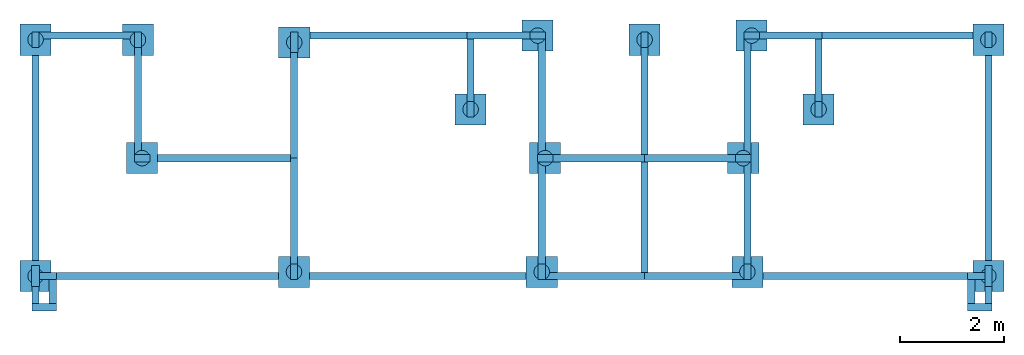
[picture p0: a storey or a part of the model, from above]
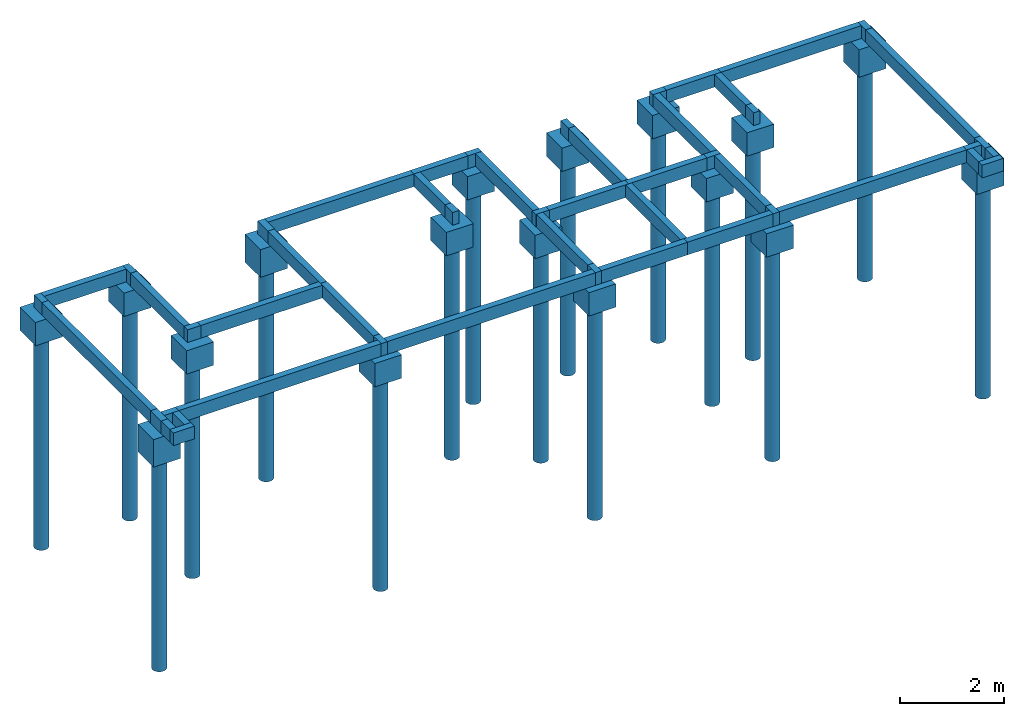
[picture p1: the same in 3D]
Properties of the parts of a building model (IFC4)

# File
Description: IFC4
Time: 2025-08-22T16:06:54
Made in: IfcPlusPlus

# IfcBuildingStorey (3)
Name | LongName | Elevation (cm)
BALDRAME (FUNDAÇÃO) | BALDRAME (FUNDAÇÃO) | 2
RESPALDO | RESPALDO | 312
PLANTIBANDA | PLANTIBANDA | 372

# IfcBeam (87)
Material: Concreto
Pset_ConcreteElementGeneral - ConcreteCover: 3 cm; ConstructionMethod: InSitu; ExposureClass: 2; StrengthClass: C-25
AltoQi_Eberick_Elemento - Elemento: Viga; Tipo: retangular
AltoQi_Eberick_Padrão - Ambiente: Externo; Cobrimento: 3 cm; Classe de concreto: C-25
AltoQi_Eberick_Cargas - Adicional (G2): 0; Solo (S): 0; Acidental (Q): 0; Água (A): 0; Subpressão (AS): 0
Pset_BeamCommon - IsExternal: yes; LoadBearing: yes
Name | In | Seção_bw (cm) | Seção_h (cm) | Elevação (cm) | Taxa de armadura | Cargas de parede (G2) | Reference
V1 | BALDRAME (FUNDAÇÃO) | 14 | 30 | 0 | 0.24 % | 526.5 | Viga C-25 - Seção Retangular 14 X 30
2 x V10 | BALDRAME (FUNDAÇÃO) | 14 | 30 | 0 | 0.24 % | 526.5 | Viga C-25 - Seção Retangular 14 X 30
2 x V11 | BALDRAME (FUNDAÇÃO) | 14 | 30 | 0 | 0.24 % | 526.5 | Viga C-25 - Seção Retangular 14 X 30
2 x V12 | BALDRAME (FUNDAÇÃO) | 14 | 30 | 0 | 0.24 % | 526.5 | Viga C-25 - Seção Retangular 14 X 30
V13 | BALDRAME (FUNDAÇÃO) | 14 | 30 | 0 | 0.24 % | 571.32 | Viga C-25 - Seção Retangular 14 X 30
2 x V14 | BALDRAME (FUNDAÇÃO) | 14 | 30 | 0 | 0.24 % | 526.5 | Viga C-25 - Seção Retangular 14 X 30
2 x V14 | BALDRAME (FUNDAÇÃO) | 14 | 30 | 0 | 0.24 % | 0 | Viga C-25 - Seção Retangular 14 X 30
2 x V15 | BALDRAME (FUNDAÇÃO) | 14 | 30 | 0 | 0.24 % | 526.5 | Viga C-25 - Seção Retangular 14 X 30
2 x V15 | BALDRAME (FUNDAÇÃO) | 14 | 30 | 0 | 0.24 % | 0 | Viga C-25 - Seção Retangular 14 X 30
2 x V2 | BALDRAME (FUNDAÇÃO) | 14 | 30 | 0 | 0.24 % | 526.5 | Viga C-25 - Seção Retangular 14 X 30
2 x V3 | BALDRAME (FUNDAÇÃO) | 14 | 30 | 0 | 0.24 % | 526.5 | Viga C-25 - Seção Retangular 14 X 30
V4 | BALDRAME (FUNDAÇÃO) | 14 | 30 | 0 | 0.24 % | 526.5 | Viga C-25 - Seção Retangular 14 X 30
2 x V5 | BALDRAME (FUNDAÇÃO) | 14 | 30 | 0 | 0.36 % | 526.5 | Viga C-25 - Seção Retangular 14 X 30
7 x V6 | BALDRAME (FUNDAÇÃO) | 14 | 30 | 0 | 0.24 % | 526.5 | Viga C-25 - Seção Retangular 14 X 30
V7 | BALDRAME (FUNDAÇÃO) | 14 | 30 | 0 | 0.24 % | 526.5 | Viga C-25 - Seção Retangular 14 X 30
2 x V8 | BALDRAME (FUNDAÇÃO) | 14 | 30 | 0 | 0.36 % | 526.5 | Viga C-25 - Seção Retangular 14 X 30
V9 | BALDRAME (FUNDAÇÃO) | 14 | 30 | 0 | 0.24 % | 526.5 | Viga C-25 - Seção Retangular 14 X 30
5 x V1 | RESPALDO | 15 | 40 | 0 | 0.17 % | 0 | Viga C-25 - Seção Retangular 15 X 40
2 x V1 | RESPALDO | 15 | 40 | 0 | 0.25 % | 0 | Viga C-25 - Seção Retangular 15 X 40
V1 | RESPALDO | 15 | 40 | 0 | 0.34 % | 0 | Viga C-25 - Seção Retangular 15 X 40
2 x V10 | RESPALDO | 14 | 30 | 0 | 0.24 % | 0 | Viga C-25 - Seção Retangular 14 X 30
V10 | RESPALDO | 14 | 30 | 0 | 0.24 % | 97.5 | Viga C-25 - Seção Retangular 14 X 30
2 x V11 | RESPALDO | 14 | 30 | 0 | 0.24 % | 0 | Viga C-25 - Seção Retangular 14 X 30
2 x V12 | RESPALDO | 14 | 30 | 0 | 0.24 % | 0 | Viga C-25 - Seção Retangular 14 X 30
V12 | RESPALDO | 14 | 30 | 0 | 0.24 % | 97.5 | Viga C-25 - Seção Retangular 14 X 30
V13 | RESPALDO | 14 | 30 | 0 | 0.24 % | 0 | Viga C-25 - Seção Retangular 14 X 30
4 x V14 | RESPALDO | 14 | 40 | 0 | 0.18 % | 0 | Viga C-25 - Seção Retangular 14 X 40
4 x V15 | RESPALDO | 14 | 40 | 0 | 0.18 % | 0 | Viga C-25 - Seção Retangular 14 X 40
V2 | RESPALDO | 14 | 30 | 0 | 0.24 % | 0 | Viga C-25 - Seção Retangular 14 X 30
V3 | RESPALDO | 14 | 30 | 0 | 0.24 % | 0 | Viga C-25 - Seção Retangular 14 X 30
V4 | RESPALDO | 14 | 30 | 0 | 0.24 % | 0 | Viga C-25 - Seção Retangular 14 X 30
2 x V5 | RESPALDO | 14 | 30 | 0 | 0.24 % | 97.5 | Viga C-25 - Seção Retangular 14 X 30
7 x V6 | RESPALDO | 14 | 40 | 0 | 0.18 % | 0 | Viga C-25 - Seção Retangular 14 X 40
V7 | RESPALDO | 14 | 30 | 0 | 0.24 % | 0 | Viga C-25 - Seção Retangular 14 X 30
2 x V8 | RESPALDO | 14 | 30 | 0 | 0.24 % | 0 | Viga C-25 - Seção Retangular 14 X 30
V9 | RESPALDO | 14 | 30 | 0 | 0.24 % | 0 | Viga C-25 - Seção Retangular 14 X 30
4 x V1 | PLANTIBANDA | 14 | 30 | 60 | 0.24 % | 0 | Viga C-25 - Seção Retangular 14 X 30
4 x V2 | PLANTIBANDA | 14 | 30 | 60 | 0.24 % | 0 | Viga C-25 - Seção Retangular 14 X 30
2 x V3 | PLANTIBANDA | 14 | 30 | 60 | 0.24 % | 0 | Viga C-25 - Seção Retangular 14 X 30
2 x V4 | PLANTIBANDA | 14 | 30 | 60 | 0.24 % | 0 | Viga C-25 - Seção Retangular 14 X 30

# IfcColumn (46)
Material: Concreto
Pset_ConcreteElementGeneral - ConcreteCover: 3 cm; ConstructionMethod: InSitu; ExposureClass: 2; StrengthClass: C-25
AltoQi_Eberick_Elemento - Elemento: Pilar; Tipo: retangular
AltoQi_Eberick_Padrão - Ambiente: Externo; Cobrimento: 3 cm; Classe de concreto: C-25
Pset_ColumnCommon - IsExternal: yes; LoadBearing: yes
Name | In | Seção_b (cm) | Seção_h (cm) | Elevação (cm) | Taxa de armadura | Taxa de compressão bruta | Taxa de compressão homogeneizada | Reference
P1 | BALDRAME (FUNDAÇÃO) | 14 | 30 | 0 | 0.75 % | 0.09 | 0.08 | Pilar C-25 - Retangular 14x30
P10 | BALDRAME (FUNDAÇÃO) | 14 | 30 | 0 | 0.75 % | 0.07 | 0.06 | Pilar C-25 - Retangular 14x30
P11 | BALDRAME (FUNDAÇÃO) | 14 | 30 | 0 | 1.12 % | 0.1 | 0.08 | Pilar C-25 - Retangular 14x30
P12 | BALDRAME (FUNDAÇÃO) | 14 | 30 | 0 | 1.12 % | 0.1 | 0.08 | Pilar C-25 - Retangular 14x30
P13 | BALDRAME (FUNDAÇÃO) | 15 | 40 | 0 | 1.64 % | 0.09 | 0.07 | Pilar C-25 - Retangular 15x40
P14 | BALDRAME (FUNDAÇÃO) | 14 | 30 | 0 | 0.75 % | 0.18 | 0.15 | Pilar C-25 - Retangular 14x30
P15 | BALDRAME (FUNDAÇÃO) | 14 | 30 | 0 | 0.75 % | 0.14 | 0.12 | Pilar C-25 - Retangular 14x30
P16 | BALDRAME (FUNDAÇÃO) | 14 | 30 | 0 | 0.75 % | 0.15 | 0.12 | Pilar C-25 - Retangular 14x30
P17 | BALDRAME (FUNDAÇÃO) | 14 | 40 | 0 | 1.75 % | 0.1 | 0.08 | Pilar C-25 - Retangular 14x40
P2 | BALDRAME (FUNDAÇÃO) | 14 | 30 | 0 | 0.75 % | 0.06 | 0.05 | Pilar C-25 - Retangular 14x30
P3 | BALDRAME (FUNDAÇÃO) | 15 | 40 | 0 | 1.64 % | 0.1 | 0.08 | Pilar C-25 - Retangular 15x40
P4 | BALDRAME (FUNDAÇÃO) | 14 | 30 | 0 | 0.75 % | 0.1 | 0.08 | Pilar C-25 - Retangular 14x30
P5 | BALDRAME (FUNDAÇÃO) | 14 | 30 | 0 | 1.12 % | 0.05 | 0.04 | Pilar C-25 - Retangular 14x30
P6 | BALDRAME (FUNDAÇÃO) | 14 | 30 | 0 | 0.75 % | 0.1 | 0.08 | Pilar C-25 - Retangular 14x30
P7 | BALDRAME (FUNDAÇÃO) | 14 | 30 | 0 | 2.34 % | 0.12 | 0.09 | Pilar C-25 - Retangular 14x30
P8 | BALDRAME (FUNDAÇÃO) | 14 | 30 | 0 | 1.12 % | 0.06 | 0.05 | Pilar C-25 - Retangular 14x30
P9 | BALDRAME (FUNDAÇÃO) | 14 | 30 | 0 | 1.12 % | 0.06 | 0.05 | Pilar C-25 - Retangular 14x30
P1 | RESPALDO | 14 | 30 | 0 | 0.75 % | 0.05 | 0.05 | Pilar C-25 - Retangular 14x30
P10 | RESPALDO | 14 | 30 | 0 | 0.75 % | 0.04 | 0.03 | Pilar C-25 - Retangular 14x30
P11 | RESPALDO | 14 | 30 | 0 | 1.12 % | 0.04 | 0.03 | Pilar C-25 - Retangular 14x30
P12 | RESPALDO | 14 | 30 | 0 | 1.12 % | 0.04 | 0.03 | Pilar C-25 - Retangular 14x30
P13 | RESPALDO | 15 | 40 | 0 | 1.64 % | 0.05 | 0.04 | Pilar C-25 - Retangular 15x40
P14 | RESPALDO | 14 | 30 | 0 | 0.75 % | 0.09 | 0.08 | Pilar C-25 - Retangular 14x30
P15 | RESPALDO | 14 | 30 | 0 | 0.75 % | 0.07 | 0.06 | Pilar C-25 - Retangular 14x30
P16 | RESPALDO | 14 | 30 | 0 | 0.75 % | 0.08 | 0.06 | Pilar C-25 - Retangular 14x30
P17 | RESPALDO | 14 | 40 | 0 | 1.75 % | 0.05 | 0.04 | Pilar C-25 - Retangular 14x40
P2 | RESPALDO | 14 | 30 | 0 | 0.75 % | 0.04 | 0.03 | Pilar C-25 - Retangular 14x30
P3 | RESPALDO | 15 | 40 | 0 | 1.64 % | 0.06 | 0.05 | Pilar C-25 - Retangular 15x40
P4 | RESPALDO | 14 | 30 | 0 | 0.75 % | 0.06 | 0.05 | Pilar C-25 - Retangular 14x30
P5 | RESPALDO | 14 | 30 | 0 | 1.12 % | 0.03 | 0.03 | Pilar C-25 - Retangular 14x30
P6 | RESPALDO | 14 | 30 | 0 | 0.75 % | 0.06 | 0.05 | Pilar C-25 - Retangular 14x30
P7 | RESPALDO | 14 | 30 | 0 | 2.34 % | 0.07 | 0.05 | Pilar C-25 - Retangular 14x30
P8 | RESPALDO | 14 | 30 | 0 | 0.75 % | 0.04 | 0.03 | Pilar C-25 - Retangular 14x30
P9 | RESPALDO | 14 | 30 | 0 | 0.75 % | 0.04 | 0.03 | Pilar C-25 - Retangular 14x30
P18 | PLANTIBANDA | 14 | 30 | 60 | 0.75 % | 0.01 | 0.01 | Pilar C-25 - Retangular 14x30
P19 | PLANTIBANDA | 14 | 30 | 60 | 0.75 % | 0.01 | 0.01 | Pilar C-25 - Retangular 14x30
P20 | PLANTIBANDA | 14 | 30 | 60 | 0.75 % | 0.01 | 0.01 | Pilar C-25 - Retangular 14x30
P21 | PLANTIBANDA | 14 | 30 | 60 | 0.75 % | 0.01 | 0.01 | Pilar C-25 - Retangular 14x30
P22 | PLANTIBANDA | 14 | 30 | 60 | 0.75 % | 0.01 | 0.01 | Pilar C-25 - Retangular 14x30
P23 | PLANTIBANDA | 14 | 30 | 60 | 0.75 % | 0.01 | 0 | Pilar C-25 - Retangular 14x30
P24 | PLANTIBANDA | 14 | 30 | 60 | 0.75 % | 0.01 | 0 | Pilar C-25 - Retangular 14x30
P25 | PLANTIBANDA | 14 | 30 | 60 | 0.75 % | 0.01 | 0.01 | Pilar C-25 - Retangular 14x30
P26 | PLANTIBANDA | 14 | 30 | 60 | 0.75 % | 0.01 | 0.01 | Pilar C-25 - Retangular 14x30
P27 | PLANTIBANDA | 14 | 30 | 60 | 0.75 % | 0.01 | 0.01 | Pilar C-25 - Retangular 14x30
P28 | PLANTIBANDA | 14 | 30 | 60 | 0.75 % | 0.01 | 0.01 | Pilar C-25 - Retangular 14x30
P29 | PLANTIBANDA | 14 | 30 | 60 | 0.75 % | 0.01 | 0.01 | Pilar C-25 - Retangular 14x30

# IfcFooting (17)
In: BALDRAME (FUNDAÇÃO)
Material: Concreto
Pset_ConcreteElementGeneral - ConcreteCover: 4.5 cm; ConstructionMethod: InSitu; ExposureClass: 2; StrengthClass: C-25
AltoQi_Eberick_Elemento - Elemento: Bloco; Tipo: 1; Seção_LB: 60 cm; Seção_LH: 60 cm; Elevação: 0 cm
AltoQi_Eberick_Padrão - Cobrimento: 4.5 cm; Classe de concreto: C-25
Pset_PileCommon - Reference: Estaca circular R30 - Concreto C-25
Pset_FootingCommon - Reference: Bloco C-25
Name
P1
P10
P11
P12
P13
P14
P15
P16
P17
P2
P3
P4
P5
P6
P7
P8
P9

# IfcPile (17)
In: BALDRAME (FUNDAÇÃO)
Material: Concreto
Pset_ConcreteElementGeneral - ConcreteCover: 4.5 cm; ConstructionMethod: InSitu; ExposureClass: 2; StrengthClass: C-25
AltoQi_Eberick_Elemento - Elemento: Bloco; Tipo: 1; Seção_LB: 60 cm; Seção_LH: 60 cm; Elevação: 0 cm
AltoQi_Eberick_Padrão - Cobrimento: 4.5 cm; Classe de concreto: C-25
Pset_PileCommon - Reference: Estaca circular R30 - Concreto C-25
Pset_FootingCommon - Reference: Bloco C-25
Name
E1-1
E10-1
E11-1
E12-1
E13-1
E14-1
E15-1
E16-1
E17-1
E2-1
E3-1
E4-1
E5-1
E6-1
E7-1
E8-1
E9-1

# IfcSlab (12)
In: RESPALDO
PredefinedType: FLOOR; Material: Concreto
Pset_ConcreteElementGeneral - ConcreteCover: 2.5 cm; ConstructionMethod: InSitu; ExposureClass: 2; StrengthClass: C-25
AltoQi_Eberick_Elemento - Elemento: Laje; Elevação: 0 cm
AltoQi_Eberick_Padrão - Ambiente: Externo; Cobrimento: 2.5 cm; Classe de concreto: C-25
AltoQi_Eberick_Cargas - Revestimento (G2): 50; Adicional (G2): 0; Solo (S): 0; Acidental (Q): 0; Água (A): 0; Subpressão (AS): 0
Pset_SlabCommon - LoadBearing: yes; IsExternal: yes; PitchAngle: 0 rad
Name | Tipo | Espessura (cm) | Reference
L1 | Maciça | 10 | Laje Maciça - h=10cm
L10 | Treliçada 1D | 12 | Laje Treliçada 1D - h=12cm
L11 | Pré-moldada | 12 | Laje Pré-moldada - h=12cm
L12 | Maciça | 10 | Laje Maciça - h=10cm
L2 | Treliçada 2D | 12 | Laje Treliçada 2D - h=12cm
L3 | Treliçada 1D | 12 | Laje Treliçada 1D - h=12cm
L4 | Treliçada 2D | 12 | Laje Treliçada 2D - h=12cm
L5 | Pré-moldada | 12 | Laje Pré-moldada - h=12cm
L6 | Treliçada 1D | 12 | Laje Treliçada 1D - h=12cm
L7 | Treliçada 1D | 12 | Laje Treliçada 1D - h=12cm
L8 | Pré-moldada | 12 | Laje Pré-moldada - h=12cm
L9 | Treliçada 2D | 12 | Laje Treliçada 2D - h=12cm
